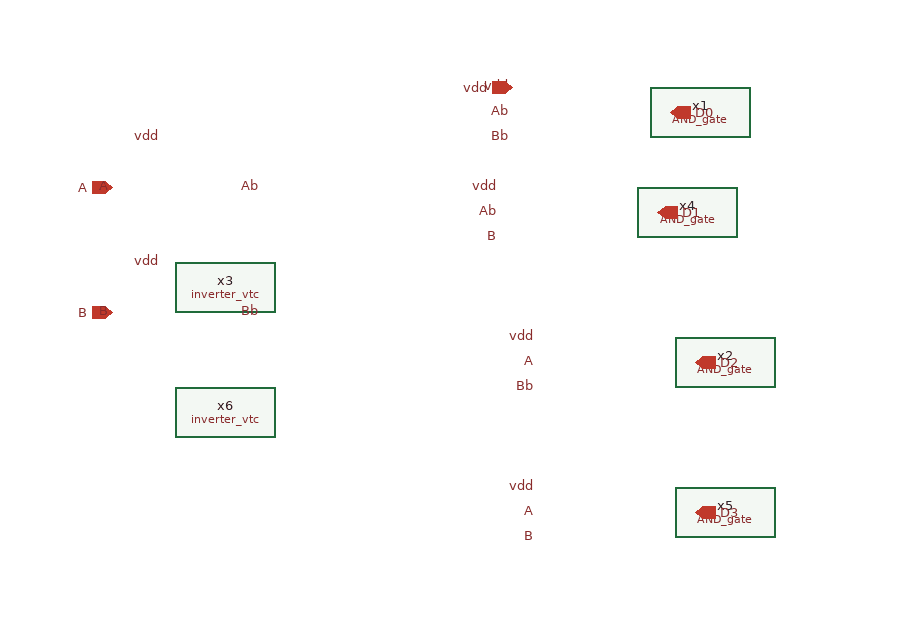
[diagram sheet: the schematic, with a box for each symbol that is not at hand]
v {xschem version=3.4.5 file_version=1.2
}
G {}
K {}
V {}
S {}
E {}
C {daVLSI_World/gates/AND_gate.sym} -322 116 0 0 {name=x1}
C {lab_pin.sym} -472 96 0 0 {name=p1 sig_type=std_logic lab=vdd}
C {lab_pin.sym} -472 116 0 0 {name=p2 sig_type=std_logic lab=Ab}
C {daVLSI_World/gates/AND_gate.sym} -302 316 0 0 {name=x2}
C {lab_pin.sym} -452 316 0 0 {name=p5 sig_type=std_logic lab=A}
C {daVLSI_World/gates/inverter_vtc.sym} -702 256 0 0 {name=x3}
C {ipin.sym} -792 176 0 0 {name=p7 lab=A}
C {lab_pin.sym} -792 176 3 0 {name=p8 sig_type=std_logic lab=A}
C {lab_pin.sym} -672 176 3 0 {name=p9 sig_type=std_logic lab=Ab}
C {lab_pin.sym} -752 136 0 0 {name=p10 sig_type=std_logic lab=vdd}
C {lab_pin.sym} -452 296 0 0 {name=p4 sig_type=std_logic lab=vdd}
C {lab_pin.sym} -452 336 0 0 {name=p13 sig_type=std_logic lab=Bb}
C {lab_pin.sym} -472 136 0 0 {name=p3 sig_type=std_logic lab=Bb}
C {opin.sym} -346 116 0 0 {name=p6 lab=D0}
C {opin.sym} -326 316 0 0 {name=p11 lab=D2}
C {ipin.sym} -472 96 0 0 {name=p14 lab=vdd}
C {daVLSI_World/gates/AND_gate.sym} -332 196 0 0 {name=x4}
C {lab_pin.sym} -482 176 0 0 {name=p15 sig_type=std_logic lab=vdd}
C {lab_pin.sym} -482 196 0 0 {name=p16 sig_type=std_logic lab=Ab}
C {daVLSI_World/gates/AND_gate.sym} -302 436 0 0 {name=x5}
C {lab_pin.sym} -452 436 0 0 {name=p17 sig_type=std_logic lab=A}
C {daVLSI_World/gates/inverter_vtc.sym} -702 356 0 0 {name=x6}
C {ipin.sym} -792 276 0 0 {name=p18 lab=B}
C {lab_pin.sym} -792 276 3 0 {name=p19 sig_type=std_logic lab=B}
C {lab_pin.sym} -672 276 3 0 {name=p20 sig_type=std_logic lab=Bb}
C {lab_pin.sym} -752 236 0 0 {name=p21 sig_type=std_logic lab=vdd}
C {lab_pin.sym} -452 416 0 0 {name=p22 sig_type=std_logic lab=vdd}
C {lab_pin.sym} -452 456 0 0 {name=p23 sig_type=std_logic lab=B}
C {lab_pin.sym} -482 216 0 0 {name=p24 sig_type=std_logic lab=B}
C {opin.sym} -356 196 0 0 {name=p25 lab=D1}
C {opin.sym} -326 436 0 0 {name=p26 lab=D3}
